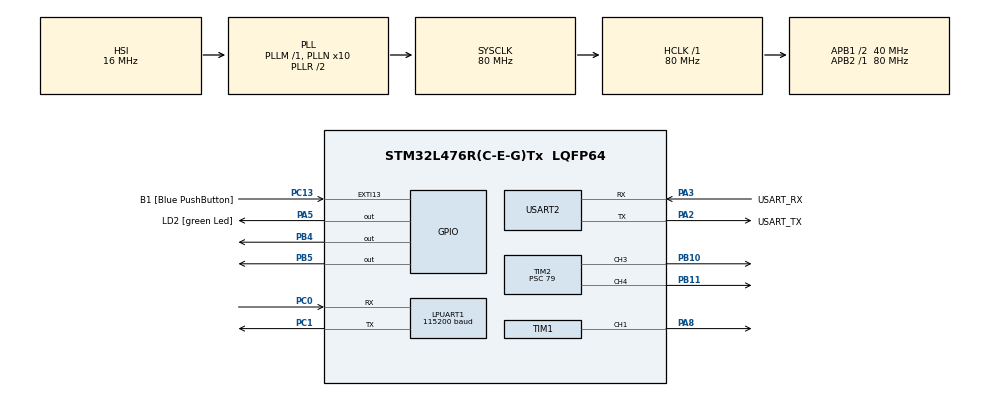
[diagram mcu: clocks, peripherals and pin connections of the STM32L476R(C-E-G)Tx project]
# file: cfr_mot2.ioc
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LPUART1.BaudRate=115200
LPUART1.WordLength=UART_WORDLENGTH_8B
Mcu.Family=STM32L4
Mcu.Name=STM32L476R(C-E-G)Tx
Mcu.Package=LQFP64
NVIC.LPUART1_IRQn=true\:0\:0\:false\:false\:true\:true\:true\:true
NVIC.PriorityGroup=NVIC_PRIORITYGROUP_4
PA13\ (JTMS-SWDIO).GPIO_Label=TMS
PA13\ (JTMS-SWDIO).Mode=Serial_Wire
PA13\ (JTMS-SWDIO).Signal=SYS_JTMS-SWDIO
PA14\ (JTCK-SWCLK).GPIO_Label=TCK
PA14\ (JTCK-SWCLK).Mode=Serial_Wire
PA14\ (JTCK-SWCLK).Signal=SYS_JTCK-SWCLK
PA2.GPIO_Label=USART_TX
PA2.GPIO_Mode=GPIO_MODE_AF_PP
PA2.GPIO_PuPd=GPIO_NOPULL
PA2.GPIO_Speed=GPIO_SPEED_FREQ_VERY_HIGH
PA2.Mode=Asynchronous
PA2.Signal=USART2_TX
PA3.GPIO_Label=USART_RX
PA3.GPIO_Mode=GPIO_MODE_AF_PP
PA3.GPIO_PuPd=GPIO_NOPULL
PA3.GPIO_Speed=GPIO_SPEED_FREQ_VERY_HIGH
PA3.Mode=Asynchronous
PA3.Signal=USART2_RX
PA5.GPIO_Label=LD2 [green Led]
PA5.GPIO_ModeDefaultOutputPP=GPIO_MODE_OUTPUT_PP
PA5.GPIO_PuPd=GPIO_NOPULL
PA5.GPIO_Speed=GPIO_SPEED_FREQ_LOW
PA5.Signal=GPIO_Output
PA8.Signal=S_TIM1_CH1
PB10.Signal=S_TIM2_CH3
PB11.Signal=S_TIM2_CH4
PB3\ (JTDO-TRACESWO).GPIO_Label=SWO
PB3\ (JTDO-TRACESWO).Signal=SYS_JTDO-SWO
PB4\ (NJTRST).Signal=GPIO_Output
PB5.Signal=GPIO_Output
PC0.Mode=Asynchronous
PC0.Signal=LPUART1_RX
PC1.Mode=Asynchronous
PC1.Signal=LPUART1_TX
PC13.GPIO_Label=B1 [Blue PushButton]
PC13.GPIO_ModeDefaultEXTI=GPIO_MODE_IT_FALLING
PC13.GPIO_PuPd=GPIO_NOPULL
PC13.Signal=GPXTI13
PC14-OSC32_IN\ (PC14).Mode=LSE-External-Oscillator
PC14-OSC32_IN\ (PC14).Signal=RCC_OSC32_IN
PC15-OSC32_OUT\ (PC15).Mode=LSE-External-Oscillator
PC15-OSC32_OUT\ (PC15).Signal=RCC_OSC32_OUT
PH0-OSC_IN\ (PH0).Mode=HSE-External-Oscillator
PH0-OSC_IN\ (PH0).Signal=RCC_OSC_IN
PH1-OSC_OUT\ (PH1).Mode=HSE-External-Oscillator
PH1-OSC_OUT\ (PH1).Signal=RCC_OSC_OUT
ProjectManager.HeapSize=0x200
ProjectManager.StackSize=0x400
ProjectManager.TargetToolchain=STM32CubeIDE
RCC.ADCFreq_Value=64000000
RCC.AHBFreq_Value=80000000
RCC.APB1CLKDivider=RCC_HCLK_DIV2
RCC.APB1Freq_Value=40000000
RCC.APB1TimFreq_Value=80000000
RCC.APB2Freq_Value=80000000
RCC.APB2TimFreq_Value=80000000
RCC.CortexFreq_Value=80000000
RCC.HCLKFreq_Value=80000000
RCC.HSE_VALUE=8000000
RCC.HSI_VALUE=16000000
RCC.MSI_VALUE=4000000
RCC.PLLN=10
RCC.PLLSourceVirtual=RCC_PLLSOURCE_HSI
RCC.PREFETCH_ENABLE=1
RCC.SYSCLKFreq_VALUE=80000000
RCC.SYSCLKSource=RCC_SYSCLKSOURCE_PLLCLK
RCC.USBFreq_Value=64000000
RCC.VCOOutputFreq_Value=160000000
SH.S_TIM1_CH1.0=TIM1_CH1,PWM Generation1 CH1
SH.S_TIM2_CH3.0=TIM2_CH3,PWM Generation3 CH3
SH.S_TIM2_CH4.0=TIM2_CH4,PWM Generation4 CH4
TIM1.Channel-PWM\ Generation1\ CH1=TIM_CHANNEL_1
TIM1.Period=1000-1
TIM1.Prescaler=1600-1
TIM2.Channel-PWM\ Generation3\ CH3=TIM_CHANNEL_3
TIM2.Channel-PWM\ Generation4\ CH4=TIM_CHANNEL_4
TIM2.Period=1999
TIM2.Prescaler=79
USART2.VirtualMode-Asynchronous=VM_ASYNC
VP_TIM1_VS_ClockSourceINT.Mode=Internal
VP_TIM2_VS_ClockSourceINT.Mode=Internal
board=NUCLEO-L476RG

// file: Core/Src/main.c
/* USER CODE BEGIN Header */
/**
  ******************************************************************************
  * @file           : main.c
  * @brief          : Main program body
  ******************************************************************************
  * @attention
  *
  * Copyright (c) 2024 STMicroelectronics.
  * All rights reserved.
  *
  * This software is licensed under terms that can be found in the LICENSE file
  * in the root directory of this software component.
  * If no LICENSE file comes with this software, it is provided AS-IS.
  *
  ******************************************************************************
  */
/* USER CODE END Header */
#include "main.h"

/* USER CODE BEGIN Includes */
#include <string.h>
#include <stdio.h>
#include "servo.h"
/* USER CODE END Includes */

UART_HandleTypeDef hlpuart1;
UART_HandleTypeDef huart2;

TIM_HandleTypeDef htim1;
TIM_HandleTypeDef htim2;

/* USER CODE BEGIN PV */
uint8_t tx_buffer[27] = "Hello Ares \n\r";
uint8_t rx_data[11];
int i = 0;

/* USER CODE END PV */

void SystemClock_Config(void);
static void MX_GPIO_Init(void);
static void MX_USART2_UART_Init(void);
static void MX_TIM2_Init(void);
static void MX_LPUART1_UART_Init(void);
static void MX_TIM1_Init(void);

int main(void)
{

  /* MCU Configuration--------------------------------------------------------*/

  /* Reset of all peripherals, Initializes the Flash interface and the Systick. */
  HAL_Init();

  /* Configure the system clock */
  SystemClock_Config();

  /* Initialize all configured peripherals */
  MX_GPIO_Init();
  MX_USART2_UART_Init();
  MX_TIM2_Init();
  MX_LPUART1_UART_Init();
  MX_TIM1_Init();
  /* USER CODE BEGIN 2 */
  HAL_TIM_PWM_Start(&htim2, TIM_CHANNEL_3); //PB10 TIM2 CH3
  HAL_TIM_PWM_Start(&htim1, TIM_CHANNEL_1); //PA 8 TIM1 CH1
  HAL_TIM_PWM_Start(&htim2, TIM_CHANNEL_4); //PB11 TIM2 CH4
  HAL_UART_Receive_IT(&hlpuart1,(uint8_t*)rx_data, 11);  // Start receiving data initially
  /* USER CODE END 2 */

  /* Infinite loop */
  /* USER CODE BEGIN WHILE */
  while (1)
  {

	      // Extraire les 4 premiers octets pour le moteur Maxon droit
	  	  char mot_maxon_dataD[4];
	  	  char direc[1];
	  	  strncpy(direc, (char *)&rx_data, 1);
	  	  //int dir_R = (int)rx_data[0];
	  	  strncpy(mot_maxon_dataD, (char *)&rx_data + 1, 4);
	  	  //mot_maxon_dataD[4] = '\0'; // Null terminate
	  	  int mot_maxon_valueD = atoi(mot_maxon_dataD);
	  	  int dir_R= atoi(direc);
	  	  mot_maxonD(mot_maxon_valueD,dir_R);

	  	  // Extraire les octets 5 à 8 pour le moteur gauche
	  	  char mot_maxon_dataG[4];
	  	  char direc_G[1];
	  	  strncpy(direc_G, (char *)&rx_data + 5, 1);
	  	  strncpy(mot_maxon_dataG, (char *)&rx_data + 6, 4);
	  	  //mot_maxon_dataG[4] = '\0'; // Null terminate
	  	  int mot_maxon_valueG = atoi(mot_maxon_dataG);
	  	  int dir_G= atoi(direc_G);
	  	  mot_maxonG(mot_maxon_valueG,dir_G);

	  	  // Extraire les octets 5 à 8 pour le servo moteur
	  	  char servo_goal_data[1];
	  	  strncpy(servo_goal_data, (char *)&rx_data + 10, 1);
	  	  //servo_goal_data[2] = '\0'; // Null terminate
	  	  int servo_goal_value = atoi(servo_goal_data);
	  	  reach_goal_servo(servo_goal_value);

	  	  // Transmission pour debug
	  	  uint8_t newline[] = "\r\n\0";

	  	  HAL_UART_Transmit(&huart2, (uint8_t *)&dir_R, sizeof(dir_R), HAL_MAX_DELAY);
	  	  HAL_UART_Transmit(&huart2, newline, sizeof(newline) - 1, HAL_MAX_DELAY);
	  	  //HAL_UART_Transmit(&huart2, (uint8_t *)mot_maxon_dataD, sizeof(mot_maxon_dataD), HAL_MAX_DELAY);
	  	  //HAL_UART_Transmit(&huart2, newline, sizeof(newline) - 1, HAL_MAX_DELAY);
	  	  //HAL_UART_Transmit(&huart2, (uint8_t *)&mot_maxon_valueD, sizeof(mot_maxon_valueD), HAL_MAX_DELAY);

	  	  //HAL_UART_Transmit(&huart2, newline, sizeof(newline) - 1, HAL_MAX_DELAY);
	  	  HAL_UART_Transmit(&huart2, (uint8_t *)&dir_G, sizeof(dir_G), HAL_MAX_DELAY);
	  	  HAL_UART_Transmit(&huart2, newline, sizeof(newline) - 1, HAL_MAX_DELAY);
	  	  //HAL_UART_Transmit(&huart2, (uint8_t *)mot_maxon_dataG, sizeof(mot_maxon_dataG), HAL_MAX_DELAY);
	  	  //HAL_UART_Transmit(&huart2, newline, sizeof(newline) - 1, HAL_MAX_DELAY);
	  	  //HAL_UART_Transmit(&huart2, (uint8_t *)&mot_maxon_valueG, sizeof(mot_maxon_valueG), HAL_MAX_DELAY);

	  	  //HAL_UART_Transmit(&huart2, newline, sizeof(newline) - 1, HAL_MAX_DELAY);
	  	  //HAL_UART_Transmit(&huart2, (uint8_t *)servo_goal_data, sizeof(servo_goal_data), HAL_MAX_DELAY);
	  	  //HAL_UART_Transmit(&huart2, newline, sizeof(newline) - 1, HAL_MAX_DELAY);
	  	  //HAL_UART_Transmit(&huart2, (uint8_t *)&servo_goal_value, sizeof(servo_goal_value), HAL_MAX_DELAY);

	  	  //HAL_UART_Transmit(&huart2, newline, sizeof(newline) - 1, HAL_MAX_DELAY);

	  	  HAL_UART_Transmit(&huart2, (uint8_t *)rx_data, sizeof(rx_data), HAL_MAX_DELAY);

	  	  HAL_UART_Transmit(&huart2, newline, sizeof(newline) - 1, HAL_MAX_DELAY);
	  	  // Réactiver la réception des données
	  	  HAL_UART_Receive_IT(&hlpuart1, rx_data, sizeof(rx_data));

    /* USER CODE END WHILE */

  }
}

void SystemClock_Config(void)
{
  RCC_OscInitTypeDef RCC_OscInitStruct = {0};
  RCC_ClkInitTypeDef RCC_ClkInitStruct = {0};

  /** Configure the main internal regulator output voltage
  */
  if (HAL_PWREx_ControlVoltageScaling(PWR_REGULATOR_VOLTAGE_SCALE1) != HAL_OK)
  {
    Error_Handler();
  }

  /** Initializes the RCC Oscillators according to the specified parameters
  * in the RCC_OscInitTypeDef structure.
  */
  RCC_OscInitStruct.OscillatorType = RCC_OSCILLATORTYPE_HSI;
  RCC_OscInitStruct.HSIState = RCC_HSI_ON;
  RCC_OscInitStruct.HSICalibrationValue = RCC_HSICALIBRATION_DEFAULT;
  RCC_OscInitStruct.PLL.PLLState = RCC_PLL_ON;
  RCC_OscInitStruct.PLL.PLLSource = RCC_PLLSOURCE_HSI;
  RCC_OscInitStruct.PLL.PLLM = 1;
  RCC_OscInitStruct.PLL.PLLN = 10;
  RCC_OscInitStruct.PLL.PLLP = RCC_PLLP_DIV7;
  RCC_OscInitStruct.PLL.PLLQ = RCC_PLLQ_DIV2;
  RCC_OscInitStruct.PLL.PLLR = RCC_PLLR_DIV2;
  if (HAL_RCC_OscConfig(&RCC_OscInitStruct) != HAL_OK)
  {
    Error_Handler();
  }

  /** Initializes the CPU, AHB and APB buses clocks
  */
  RCC_ClkInitStruct.ClockType = RCC_CLOCKTYPE_HCLK|RCC_CLOCKTYPE_SYSCLK
                              |RCC_CLOCKTYPE_PCLK1|RCC_CLOCKTYPE_PCLK2;
  RCC_ClkInitStruct.SYSCLKSource = RCC_SYSCLKSOURCE_PLLCLK;
  RCC_ClkInitStruct.AHBCLKDivider = RCC_SYSCLK_DIV1;
  RCC_ClkInitStruct.APB1CLKDivider = RCC_HCLK_DIV2;
  RCC_ClkInitStruct.APB2CLKDivider = RCC_HCLK_DIV1;

  if (HAL_RCC_ClockConfig(&RCC_ClkInitStruct, FLASH_LATENCY_4) != HAL_OK)
  {
    Error_Handler();
  }
}

static void MX_LPUART1_UART_Init(void)
{

  hlpuart1.Instance = LPUART1;
  hlpuart1.Init.BaudRate = 115200;
  hlpuart1.Init.WordLength = UART_WORDLENGTH_8B;
  hlpuart1.Init.StopBits = UART_STOPBITS_1;
  hlpuart1.Init.Parity = UART_PARITY_NONE;
  hlpuart1.Init.Mode = UART_MODE_TX_RX;
  hlpuart1.Init.HwFlowCtl = UART_HWCONTROL_NONE;
  hlpuart1.Init.OneBitSampling = UART_ONE_BIT_SAMPLE_DISABLE;
  hlpuart1.AdvancedInit.AdvFeatureInit = UART_ADVFEATURE_NO_INIT;
  if (HAL_UART_Init(&hlpuart1) != HAL_OK)
  {
    Error_Handler();
  }

}

static void MX_USART2_UART_Init(void)
{

  huart2.Instance = USART2;
  huart2.Init.BaudRate = 115200;
  huart2.Init.WordLength = UART_WORDLENGTH_8B;
  huart2.Init.StopBits = UART_STOPBITS_1;
  huart2.Init.Parity = UART_PARITY_NONE;
  huart2.Init.Mode = UART_MODE_TX_RX;
  huart2.Init.HwFlowCtl = UART_HWCONTROL_NONE;
  huart2.Init.OverSampling = UART_OVERSAMPLING_16;
  huart2.Init.OneBitSampling = UART_ONE_BIT_SAMPLE_DISABLE;
  huart2.AdvancedInit.AdvFeatureInit = UART_ADVFEATURE_NO_INIT;
  if (HAL_UART_Init(&huart2) != HAL_OK)
  {
    Error_Handler();
  }

}

static void MX_TIM1_Init(void)
{

  TIM_ClockConfigTypeDef sClockSourceConfig = {0};
  TIM_MasterConfigTypeDef sMasterConfig = {0};
  TIM_OC_InitTypeDef sConfigOC = {0};
  TIM_BreakDeadTimeConfigTypeDef sBreakDeadTimeConfig = {0};

  htim1.Instance = TIM1;
  htim1.Init.Prescaler = 1600-1;
  htim1.Init.CounterMode = TIM_COUNTERMODE_UP;
  htim1.Init.Period = 1000-1;
  htim1.Init.ClockDivision = TIM_CLOCKDIVISION_DIV1;
  htim1.Init.RepetitionCounter = 0;
  htim1.Init.AutoReloadPreload = TIM_AUTORELOAD_PRELOAD_DISABLE;
  if (HAL_TIM_Base_Init(&htim1) != HAL_OK)
  {
    Error_Handler();
  }
  sClockSourceConfig.ClockSource = TIM_CLOCKSOURCE_INTERNAL;
  if (HAL_TIM_ConfigClockSource(&htim1, &sClockSourceConfig) != HAL_OK)
  {
    Error_Handler();
  }
  if (HAL_TIM_PWM_Init(&htim1) != HAL_OK)
  {
    Error_Handler();
  }
  sMasterConfig.MasterOutputTrigger = TIM_TRGO_RESET;
  sMasterConfig.MasterOutputTrigger2 = TIM_TRGO2_RESET;
  sMasterConfig.MasterSlaveMode = TIM_MASTERSLAVEMODE_DISABLE;
  if (HAL_TIMEx_MasterConfigSynchronization(&htim1, &sMasterConfig) != HAL_OK)
  {
    Error_Handler();
  }
  sConfigOC.OCMode = TIM_OCMODE_PWM1;
  sConfigOC.Pulse = 0;
  sConfigOC.OCPolarity = TIM_OCPOLARITY_HIGH;
  sConfigOC.OCNPolarity = TIM_OCNPOLARITY_HIGH;
  sConfigOC.OCFastMode = TIM_OCFAST_DISABLE;
  sConfigOC.OCIdleState = TIM_OCIDLESTATE_RESET;
  sConfigOC.OCNIdleState = TIM_OCNIDLESTATE_RESET;
  if (HAL_TIM_PWM_ConfigChannel(&htim1, &sConfigOC, TIM_CHANNEL_1) != HAL_OK)
  {
    Error_Handler();
  }
  sBreakDeadTimeConfig.OffStateRunMode = TIM_OSSR_DISABLE;
  sBreakDeadTimeConfig.OffStateIDLEMode = TIM_OSSI_DISABLE;
  sBreakDeadTimeConfig.LockLevel = TIM_LOCKLEVEL_OFF;
  sBreakDeadTimeConfig.DeadTime = 0;
  sBreakDeadTimeConfig.BreakState = TIM_BREAK_DISABLE;
  sBreakDeadTimeConfig.BreakPolarity = TIM_BREAKPOLARITY_HIGH;
  sBreakDeadTimeConfig.BreakFilter = 0;
  sBreakDeadTimeConfig.Break2State = TIM_BREAK2_DISABLE;
  sBreakDeadTimeConfig.Break2Polarity = TIM_BREAK2POLARITY_HIGH;
  sBreakDeadTimeConfig.Break2Filter = 0;
  sBreakDeadTimeConfig.AutomaticOutput = TIM_AUTOMATICOUTPUT_DISABLE;
  if (HAL_TIMEx_ConfigBreakDeadTime(&htim1, &sBreakDeadTimeConfig) != HAL_OK)
  {
    Error_Handler();
  }
  HAL_TIM_MspPostInit(&htim1);

}

static void MX_TIM2_Init(void)
{

  TIM_ClockConfigTypeDef sClockSourceConfig = {0};
  TIM_MasterConfigTypeDef sMasterConfig = {0};
  TIM_OC_InitTypeDef sConfigOC = {0};

  htim2.Instance = TIM2;
  htim2.Init.Prescaler = 79;
  htim2.Init.CounterMode = TIM_COUNTERMODE_UP;
  htim2.Init.Period = 1999;
  htim2.Init.ClockDivision = TIM_CLOCKDIVISION_DIV1;
  htim2.Init.AutoReloadPreload = TIM_AUTORELOAD_PRELOAD_DISABLE;
  if (HAL_TIM_Base_Init(&htim2) != HAL_OK)
  {
    Error_Handler();
  }
  sClockSourceConfig.ClockSource = TIM_CLOCKSOURCE_INTERNAL;
  if (HAL_TIM_ConfigClockSource(&htim2, &sClockSourceConfig) != HAL_OK)
  {
    Error_Handler();
  }
  if (HAL_TIM_PWM_Init(&htim2) != HAL_OK)
  {
    Error_Handler();
  }
  sMasterConfig.MasterOutputTrigger = TIM_TRGO_RESET;
  sMasterConfig.MasterSlaveMode = TIM_MASTERSLAVEMODE_DISABLE;
  if (HAL_TIMEx_MasterConfigSynchronization(&htim2, &sMasterConfig) != HAL_OK)
  {
    Error_Handler();
  }
  sConfigOC.OCMode = TIM_OCMODE_PWM1;
  sConfigOC.Pulse = 0;
  sConfigOC.OCPolarity = TIM_OCPOLARITY_HIGH;
  sConfigOC.OCFastMode = TIM_OCFAST_DISABLE;
  if (HAL_TIM_PWM_ConfigChannel(&htim2, &sConfigOC, TIM_CHANNEL_3) != HAL_OK)
  {
    Error_Handler();
  }
  if (HAL_TIM_PWM_ConfigChannel(&htim2, &sConfigOC, TIM_CHANNEL_4) != HAL_OK)
  {
    Error_Handler();
  }
  HAL_TIM_MspPostInit(&htim2);

}

static void MX_GPIO_Init(void)
{
  GPIO_InitTypeDef GPIO_InitStruct = {0};

  /* GPIO Ports Clock Enable */
  __HAL_RCC_GPIOC_CLK_ENABLE();
  __HAL_RCC_GPIOH_CLK_ENABLE();
  __HAL_RCC_GPIOA_CLK_ENABLE();
  __HAL_RCC_GPIOB_CLK_ENABLE();

  /*Configure GPIO pin Output Level */
  HAL_GPIO_WritePin(LD2_GPIO_Port, LD2_Pin, GPIO_PIN_RESET);

  /*Configure GPIO pin Output Level */
  HAL_GPIO_WritePin(GPIOB, GPIO_PIN_4|GPIO_PIN_5|GPIO_PIN_8|GPIO_PIN_9, GPIO_PIN_RESET);

  /*Configure GPIO pin : B1_Pin */
  GPIO_InitStruct.Pin = B1_Pin;
  GPIO_InitStruct.Mode = GPIO_MODE_IT_FALLING;
  GPIO_InitStruct.Pull = GPIO_NOPULL;
  HAL_GPIO_Init(B1_GPIO_Port, &GPIO_InitStruct);

  /*Configure GPIO pin : LD2_Pin */
  GPIO_InitStruct.Pin = LD2_Pin;
  GPIO_InitStruct.Mode = GPIO_MODE_OUTPUT_PP;
  GPIO_InitStruct.Pull = GPIO_NOPULL;
  GPIO_InitStruct.Speed = GPIO_SPEED_FREQ_LOW;
  HAL_GPIO_Init(LD2_GPIO_Port, &GPIO_InitStruct);

  /*Configure GPIO pins : PB4 PB5 PB8 PB9 */
  GPIO_InitStruct.Pin = GPIO_PIN_4|GPIO_PIN_5|GPIO_PIN_8|GPIO_PIN_9;
  GPIO_InitStruct.Mode = GPIO_MODE_OUTPUT_PP;
  GPIO_InitStruct.Pull = GPIO_NOPULL;
  GPIO_InitStruct.Speed = GPIO_SPEED_FREQ_LOW;
  HAL_GPIO_Init(GPIOB, &GPIO_InitStruct);

}

/* USER CODE BEGIN 4 */
void HAL_UART_RxCpltCallback(UART_HandleTypeDef *huart)
{

}
/* USER CODE END 4 */

void Error_Handler(void)
{
  __disable_irq();
  while (1)
  {
  }
}
